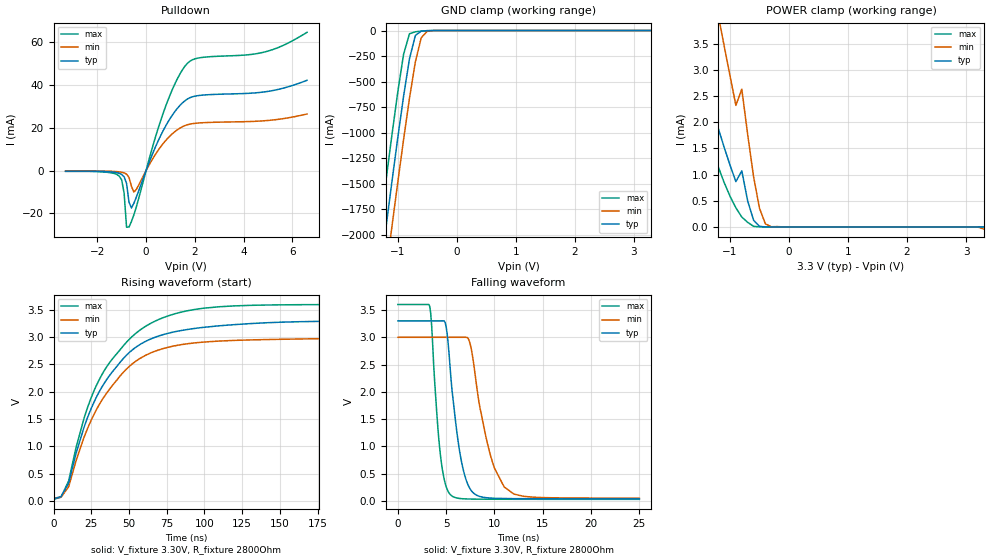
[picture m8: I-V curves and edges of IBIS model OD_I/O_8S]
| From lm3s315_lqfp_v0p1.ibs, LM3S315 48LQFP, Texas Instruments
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[Model]   OD_I/O_8S
Model_type   I/O_open_drain
Polarity   Inverting
Vinl = 1.26
Vinh = 2.04
Vmeas = 1.65
Rref = 2800
Vref = 3.3
| variable   typ   min   max
C_comp   9.739pF   9.739pF   9.739pF
[Model Spec]
Vinh+   1.91   1.78   2.04
Vinh-   1.90   1.76   2.03
Vinl+   1.40   1.27   1.54
Vinl-   1.39   1.26   1.53
| variable   typ   min   max
[Temperature Range]  25   85   -40
[Voltage Range]   3.3V   3.0V   3.6V
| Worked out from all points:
|   slope of the pulldown table from 0 to 0.495 V, typ, clamps not added: 35.8 ohm
|   GND clamp passes 1 mA (typ) near -0.48 V on its own axis
|   POWER clamp passes 1 mA (typ) near -0.79 V on its own axis
|   falling waveform, V_fixture 3.30V, R_fixture 2800Ohm: 20-80 % time 1.3ns typ, 2ns min, 876ps max; typ from 3.3 V to 0.038 V
|   rising waveform, V_fixture 3.30V, R_fixture 2800Ohm: 20-80 % time 34.2ns typ, 34ns min, 34.6ns max; typ from 0.038 V to 3.3 V
[Pulldown]
|  Voltage   I(typ)   I(min)   I(max)
-3.3V     -256.6uA   -145.6uA   -364.5uA
-1.1V     -1.273mA   -587.5uA   -2.567mA
-900mV    -2.885mA   -1.061mA   -10.54mA
-800mV    -5.993mA   -1.67mA    -26.39mA
-700mV    -14.71mA   -3.215mA   -26.33mA
-600mV    -17.43mA   -7.321mA   -23.73mA
-500mV    -15.26mA   -10mA      -20.66mA
700mV     18.62mA    12.61mA    26.75mA
1.2V      27.84mA    18.36mA    40.91mA
1.7V      33.44mA    21.41mA    50.13mA
4.9V      36.8mA     23.3mA     55.47mA
6.6V      42.15mA    26.42mA    64.53mA
[GND Clamp]
|  Voltage   I(typ)   I(min)   I(max)
-3.3V     -11.72A    -12.12A    -11.3A
-1.4V     -2.845A    -3.285A    -2.387A
-1.3V     -2.39A     -2.831A    -1.93A
-1.2V     -1.938A    -2.38A     -1.478A
-1.1V     -1.494A    -1.934A    -1.036A
-1V       -1.059A    -1.496A    -610.6mA
-900mV    -645mA     -1.069A    -232.9mA
-800mV    -277.1mA   -664.4mA   -31.59mA
-700mV    -48.56mA   -306.6mA   -12.09mA
-600mV    -5.558mA   -70.2mA    -6.272mA
-500mV    -1.167mA   -7.879mA   -2.167mA
3.3V      2.282nA    3.101uA    451.3pA
[POWER Clamp]
|  Voltage   I(typ)   I(min)   I(max)
-3.3V     12.41mA    17.26mA    12.22mA
-1.9V     4.919mA    8.328mA    4.074mA
-1.8V     4.445mA    7.705mA    3.587mA
-1.6V     3.533mA    6.47mA     2.675mA
-1.2V     1.89mA     4.055mA    1.153mA
-1.1V     1.526mA    3.468mA    851.4uA
-900mV    866.3uA    2.324mA    364.9uA
-800mV    1.074mA    2.635mA    188.8uA
-600mV    127.8uA    958.5uA    11.41uA
-500mV    11.24uA    355.9uA    954.7nA
-300mV    9.515nA    3.101uA    1.472nA
3.3V      -104.7pA   -40.34uA   119.2pA
[Ramp]
| variable   typ   min   max
dV/dt_f   1.96/1.30n   1.77/2.00n   2.14/0.88n
dV/dt_r   1.96/34.20n   1.77/34.00n   2.14/34.57n
R_load = 2800Ohm
[Falling Waveform]
V_fixture = 3.30V
V_fixture_min = 3.00V
V_fixture_max = 3.60V
R_fixture = 2800Ohm
|   Time   V(typ)   V(min)   V(max)
0s        3.3V       2.999V     3.6V
3.3ns     3.3V       2.999V     3.565V
4.4ns     3.3V       2.999V     841.6mV
5ns       3.185V     2.999V     258.6mV
5.5ns     2.23V      2.999V     103.6mV
6.4ns     899.7mV    2.999V     45.24mV
7.3ns     278.6mV    2.968V     35.71mV
9.3ns     56.76mV    1.03V      31.65mV
11ns      44.31mV    257mV      30.72mV
25ns      37.97mV    50.46mV    29.46mV
[Rising Waveform]
V_fixture = 3.30V
V_fixture_min = 3.00V
V_fixture_max = 3.60V
R_fixture = 2800Ohm
|   Time   V(typ)   V(min)   V(max)
0s        38.08mV    50.73mV    29.48mV
5ns       80.56mV    68.14mV    69.02mV
10ns      327.1mV    259.1mV    364.9mV
20ns      1.331V     1.15V      1.493V
32ns      2.083V     1.844V     2.31V
49ns      2.688V     2.434V     2.927V
65ns      2.974V     2.718V     3.262V
85ns      3.124V     2.865V     3.462V
110ns     3.21V      2.93V      3.558V
250ns     3.298V     2.994V     3.599V
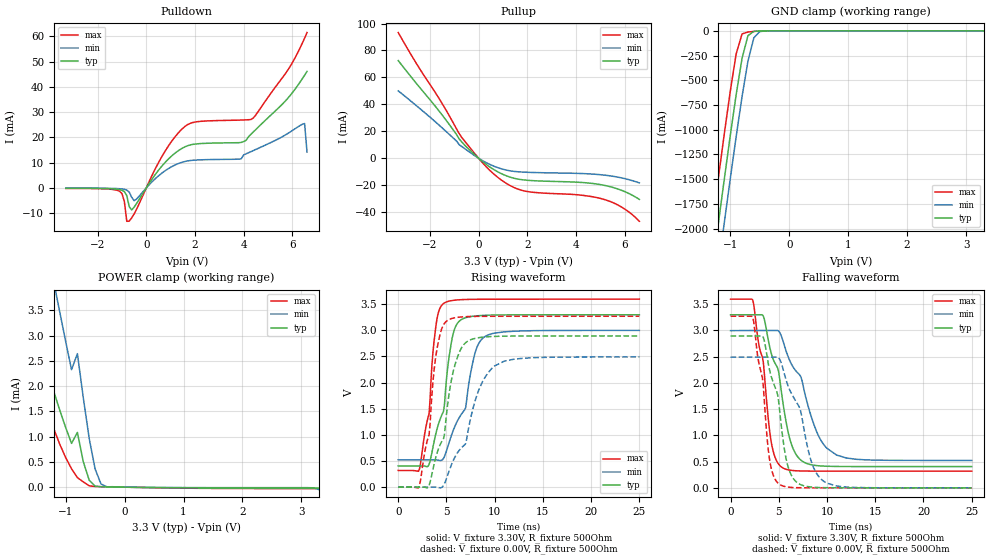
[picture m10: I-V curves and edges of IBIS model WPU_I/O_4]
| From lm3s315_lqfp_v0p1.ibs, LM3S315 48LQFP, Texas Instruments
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[Model]   WPU_I/O_4
Model_type   I/O
Vinl = 1.26
Vinh = 2.04
Vmeas = 1.65
| variable   typ   min   max
C_comp   9.739pF   9.739pF   9.739pF
[Model Spec]
Vinh+   1.91   1.78   2.04
Vinh-   1.90   1.76   2.03
Vinl+   1.40   1.27   1.54
Vinl-   1.39   1.26   1.53
| variable   typ   min   max
[Temperature Range]  25   85   -40
[Voltage Range]   3.3V   3.0V   3.6V
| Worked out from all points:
|   slope of the pulldown table from 0 to 0.495 V, typ, clamps not added: 71.5 ohm
|   slope of the pullup table from 0 to 0.495 V, typ, clamps not added: 71.7 ohm
|   GND clamp passes 1 mA (typ) near -0.48 V on its own axis
|   POWER clamp passes 1 mA (typ) near -0.79 V on its own axis
|   falling waveform, V_fixture 3.30V, R_fixture 500Ohm: 20-80 % time 2.05ns typ, 3.09ns min, 1.37ns max; typ from 3.3 V to 0.405 V
|   rising waveform, V_fixture 3.30V, R_fixture 500Ohm: 20-80 % time 1.61ns typ, 2.31ns min, 1.11ns max; typ from 0.405 V to 3.3 V
|   falling waveform, V_fixture 0.00V, R_fixture 500Ohm: 20-80 % time 1.77ns typ, 2.51ns min, 1.22ns max; typ from 2.89 V to 0 V
|   rising waveform, V_fixture 0.00V, R_fixture 500Ohm: 20-80 % time 1.94ns typ, 2.99ns min, 1.25ns max; typ from 0 V to 2.89 V
[Pulldown]
|  Voltage   I(typ)   I(min)   I(max)
-3.3V     -128.1uA   -72.7uA    -182uA
-1.1V     -635.5uA   -293.2uA   -1.281mA
-900mV    -1.441mA   -529.5uA   -5.265mA
-800mV    -2.994mA   -834uA     -13.18mA
-700mV    -7.352mA   -1.606mA   -13.14mA
-500mV    -7.614mA   -4.997mA   -10.31mA
600mV     8.196mA    5.576mA    11.73mA
1.4V      15.29mA    9.963mA    22.68mA
3.9V      18.05mA    11.57mA    26.9mA
4.4V      22.22mA    14.83mA    27.78mA
6.5V      44.63mA    25.52mA    59.31mA
6.6V      46.13mA    14.23mA    61.52mA
[Pullup]
|  Voltage   I(typ)   I(min)   I(max)
-3.3V     72.5mA     49.99mA    93.3mA
-2.5V     54.35mA    38.2mA     68.78mA
-1.6V     34.54mA    24.22mA    43.68mA
-700mV    12.28mA    8.827mA    15.66mA
100mV     -1.551mA   -1.116mA   -2.115mA
800mV     -10.21mA   -7.07mA    -14.36mA
1.4V      -14.59mA   -9.626mA   -21.26mA
1.9V      -16.18mA   -10.35mA   -24.37mA
4.2V      -17.95mA   -11.33mA   -27.39mA
5.2V      -20.26mA   -12.61mA   -30.84mA
5.9V      -24.04mA   -14.71mA   -36.57mA
6.6V      -30.54mA   -18.34mA   -46.81mA
[GND Clamp]
|  Voltage   I(typ)   I(min)   I(max)
-3.3V     -11.72A    -12.12A    -11.3A
-1.4V     -2.845A    -3.285A    -2.387A
-1.3V     -2.39A     -2.831A    -1.93A
-1.2V     -1.938A    -2.38A     -1.478A
-1.1V     -1.494A    -1.934A    -1.036A
-1V       -1.059A    -1.496A    -610.6mA
-900mV    -645mA     -1.069A    -232.9mA
-800mV    -277.1mA   -664.4mA   -31.6mA
-700mV    -48.56mA   -306.6mA   -12.11mA
-600mV    -5.565mA   -70.2mA    -6.295mA
-500mV    -1.181mA   -7.883mA   -2.192mA
3.3V      2.282nA    6.919uA    -6.848uA
[POWER Clamp]
|  Voltage   I(typ)   I(min)   I(max)
-3.3V     12.41mA    17.26mA    12.22mA
-1.9V     4.919mA    8.328mA    4.074mA
-1.8V     4.445mA    7.705mA    3.587mA
-1.6V     3.533mA    6.47mA     2.675mA
-1.2V     1.89mA     4.055mA    1.153mA
-1.1V     1.526mA    3.468mA    851.4uA
-900mV    866.3uA    2.324mA    364.9uA
-800mV    1.083mA    2.641mA    188.8uA
-600mV    138.2uA    964.3uA    27.06uA
-500mV    20.59uA    361.5uA    14.14uA
-300mV    5.5uA      6.919uA    7.727uA
3.3V      -16.69uA   -49.93uA   -27.55uA
[Ramp]
| variable   typ   min   max
dV/dt_f   1.73/2.05n   1.48/3.09n   1.97/1.37n
dV/dt_r   1.74/1.94n   1.49/2.99n   1.96/1.25n
R_load = 500Ohm
[Falling Waveform]
V_fixture = 3.30V
V_fixture_min = 3.00V
V_fixture_max = 3.60V
R_fixture = 500Ohm
|   Time   V(typ)   V(min)   V(max)
0s        3.297V     2.995V     3.595V
2.3ns     3.297V     2.997V     3.581V
3.4ns     3.271V     2.998V     2.39V
4.2ns     2.577V     2.998V     893.2mV
5.3ns     1.792V     2.875V     394.2mV
6.1ns     962.2mV    2.44V      338.8mV
6.9ns     607.4mV    2.202V     324.6mV
9.1ns     421.1mV    998.9mV    318.9mV
11ns      407.9mV    624.6mV    318.6mV
25ns      405.4mV    522.4mV    318.5mV
[Rising Waveform]
V_fixture = 3.30V
V_fixture_min = 3.00V
V_fixture_max = 3.60V
R_fixture = 500Ohm
|   Time   V(typ)   V(min)   V(max)
0s        405.4mV    522.4mV    318.5mV
2.2ns     405.4mV    522.4mV    342.1mV
3.2ns     434.8mV    522.4mV    1.403V
3.6ns     761.7mV    522.3mV    2.579V
4ns       1.095V     520.9mV    3.199V
4.7ns     1.452V     551.4mV    3.512V
5.2ns     2.393V     808.8mV    3.555V
5.9ns     3.052V     1.174V     3.578V
9ns       3.287V     2.882V     3.595V
25ns      3.298V     2.999V     3.597V
[Falling Waveform]
V_fixture = 0.00V
V_fixture_min = 0.00V
V_fixture_max = 0.00V
R_fixture = 500Ohm
|   Time   V(typ)   V(min)   V(max)
0s        2.893V     2.49V      3.27V
2.3ns     2.893V     2.491V     3.255V
3.4ns     2.865V     2.491V     1.929V
4.1ns     2.201V     2.491V     478mV
5.1ns     1.455V     2.448V     64.64mV
5.7ns     611mV      2.094V     22.44mV
6.4ns     209.3mV    1.769V     7.462mV
8.5ns     13.92mV    435.2mV    569.2uV
9.7ns     4.121mV    120.7mV    206.4uV
25ns      18.45uV    33.67uV    11.46uV
[Rising Waveform]
V_fixture = 0.00V
V_fixture_min = 0.00V
V_fixture_max = 0.00V
R_fixture = 500Ohm
|   Time   V(typ)   V(min)   V(max)
0s        277.5uV    4.41mV     16.89uV
2.2ns     48.93uV    1.08mV     26.48mV
3.2ns     32.91mV    595.4uV    1V
4ns       636.7mV    -1.097mV   2.624V
4.7ns     929mV      32.28mV    3.107V
5.1ns     1.546V     213.9mV    3.188V
6.7ns     2.704V     779.6mV    3.258V
8.4ns     2.861V     1.878V     3.267V
10ns      2.884V     2.32V      3.269V
25ns      2.893V     2.49V      3.269V
